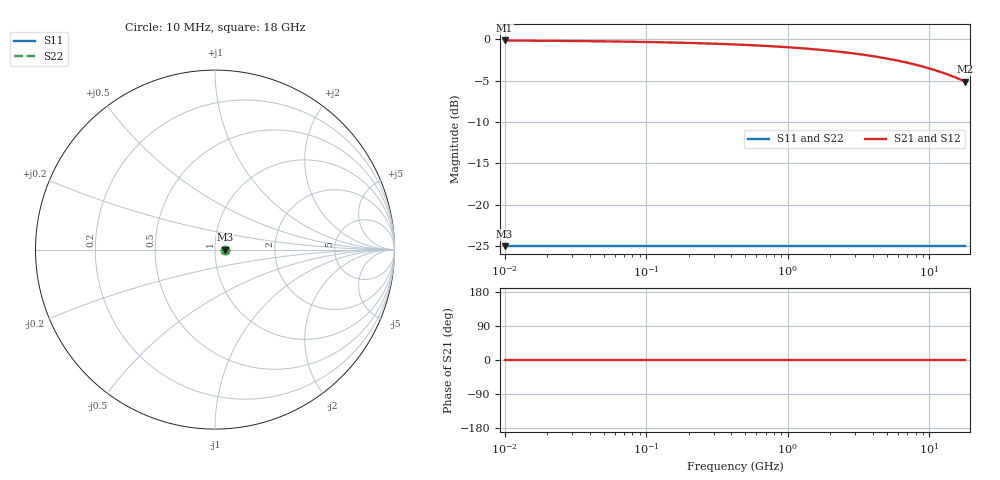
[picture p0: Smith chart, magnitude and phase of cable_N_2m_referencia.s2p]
! CAL-ELEKTRA — ESPECIFICACIÓN SINTÉTICA DE EJEMPLO: no es la de ningún fabricante.
! Cable N de 2 m: |S21| típico (curva de referencia para la comprobación ± tolerancia)
# GHZ S DB R 50
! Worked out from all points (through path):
!   300 points, 10 MHz to 18 GHz, reference 50 ohm
!   highest |S21| = -0.13 dB at 10 MHz (marker M1); lowest = -5.1 dB at 18 GHz (marker M2)
!   lowest |S11| = -25.0 dB at 10 MHz (marker M3), VSWR 1.12, Z = 56 + j0 ohm
!   |S11| at or under -10 dB: start of sweep to end of sweep
!   |S22| runs from -25.0 to -25.0 dB; largest |S21 - S12| = 0
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0.01  -25.00 0.0  -0.13 0.0  -0.13 0.0  -25.00 0.0
0.03502353  -25.00 0.0  -0.20 0.0  -0.20 0.0  -25.00 0.0
0.06720895  -25.00 0.0  -0.27 0.0  -0.27 0.0  -25.00 0.0
0.1226648  -25.00 0.0  -0.34 0.0  -0.34 0.0  -25.00 0.0
0.2353895  -25.00 0.0  -0.46 0.0  -0.46 0.0  -25.00 0.0
0.4296154  -25.00 0.0  -0.62 0.0  -0.62 0.0  -25.00 0.0
0.5951322  -25.00 0.0  -0.73 0.0  -0.73 0.0  -25.00 0.0
0.8244172  -25.00 0.0  -0.86 0.0  -0.86 0.0  -25.00 0.0
1.113765  -25.00 0.0  -1.01 0.0  -1.01 0.0  -25.00 0.0
1.504665  -25.00 0.0  -1.18 0.0  -1.18 0.0  -25.00 0.0
2.084363  -25.00 0.0  -1.41 0.0  -1.41 0.0  -25.00 0.0
2.8874  -25.00 0.0  -1.69 0.0  -1.69 0.0  -25.00 0.0
3.900797  -25.00 0.0  -2.00 0.0  -2.00 0.0  -25.00 0.0
5.269868  -25.00 0.0  -2.38 0.0  -2.38 0.0  -25.00 0.0
6.28073  -25.00 0.0  -2.65 0.0  -2.65 0.0  -25.00 0.0
7.300176  -25.00 0.0  -2.90 0.0  -2.90 0.0  -25.00 0.0
8.70049  -25.00 0.0  -3.22 0.0  -3.22 0.0  -25.00 0.0
10.1127  -25.00 0.0  -3.54 0.0  -3.54 0.0  -25.00 0.0
11.75412  -25.00 0.0  -3.88 0.0  -3.88 0.0  -25.00 0.0
13.66197  -25.00 0.0  -4.27 0.0  -4.27 0.0  -25.00 0.0
15.87949  -25.00 0.0  -4.71 0.0  -4.71 0.0  -25.00 0.0
18  -25.00 0.0  -5.11 0.0  -5.11 0.0  -25.00 0.0
